VERSION 5.7 ;
  NOWIREEXTENSIONATPIN ON ;
  DIVIDERCHAR "/" ;
  BUSBITCHARS "[]" ;
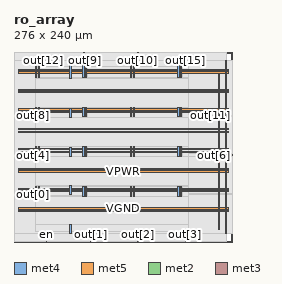
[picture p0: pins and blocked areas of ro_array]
MACRO ro_array
  CLASS BLOCK ;
  FOREIGN ro_array ;
  ORIGIN 0.000 0.000 ;
  SIZE 276.000 BY 240.000 ;
  PIN VGND
    DIRECTION INOUT ;
    USE GROUND ;
    PORT
      LAYER met4 ;
        RECT 30.320 58.040 31.920 70.040 ;
    END
    PORT
      LAYER met4 ;
        RECT 30.320 108.040 31.920 120.040 ;
    END
    PORT
      LAYER met4 ;
        RECT 30.320 158.040 31.920 170.040 ;
    END
    PORT
      LAYER met4 ;
        RECT 30.320 208.040 31.920 228.720 ;
    END
    PORT
      LAYER met4 ;
        RECT 90.320 58.040 91.920 70.040 ;
    END
    PORT
      LAYER met4 ;
        RECT 90.320 108.040 91.920 120.040 ;
    END
    PORT
      LAYER met4 ;
        RECT 90.320 158.040 91.920 170.040 ;
    END
    PORT
      LAYER met4 ;
        RECT 90.320 208.040 91.920 228.720 ;
    END
    PORT
      LAYER met4 ;
        RECT 150.320 58.040 151.920 70.040 ;
    END
    PORT
      LAYER met4 ;
        RECT 150.320 108.040 151.920 120.040 ;
    END
    PORT
      LAYER met4 ;
        RECT 150.320 158.040 151.920 170.040 ;
    END
    PORT
      LAYER met4 ;
        RECT 150.320 208.040 151.920 228.720 ;
    END
    PORT
      LAYER met4 ;
        RECT 210.320 58.040 211.920 70.040 ;
    END
    PORT
      LAYER met4 ;
        RECT 210.320 108.040 211.920 120.040 ;
    END
    PORT
      LAYER met4 ;
        RECT 210.320 158.040 211.920 170.040 ;
    END
    PORT
      LAYER met4 ;
        RECT 210.320 208.040 211.920 228.720 ;
    END
    PORT
      LAYER met5 ;
        RECT 5.520 41.540 270.480 43.140 ;
    END
    PORT
      LAYER met5 ;
        RECT 5.520 66.540 270.480 68.140 ;
    END
    PORT
      LAYER met5 ;
        RECT 5.520 91.540 270.480 93.140 ;
    END
    PORT
      LAYER met5 ;
        RECT 5.520 116.540 270.480 118.140 ;
    END
    PORT
      LAYER met5 ;
        RECT 5.520 141.540 270.480 143.140 ;
    END
    PORT
      LAYER met5 ;
        RECT 5.520 166.540 270.480 168.140 ;
    END
    PORT
      LAYER met5 ;
        RECT 5.520 191.540 270.480 193.140 ;
    END
    PORT
      LAYER met5 ;
        RECT 5.520 216.540 270.480 218.140 ;
    END
    PORT
      LAYER met4 ;
        RECT 70.500 10.640 72.100 22.000 ;
    END
    PORT
      LAYER met4 ;
        RECT 70.500 59.600 72.100 70.960 ;
    END
    PORT
      LAYER met4 ;
        RECT 70.500 108.560 72.100 119.920 ;
    END
    PORT
      LAYER met4 ;
        RECT 70.500 157.520 72.100 168.880 ;
    END
    PORT
      LAYER met4 ;
        RECT 70.500 206.480 72.100 223.280 ;
    END
    PORT
      LAYER met4 ;
        RECT 258.180 16.080 259.780 212.400 ;
    END
  END VGND
  PIN VPWR
    DIRECTION INOUT ;
    USE POWER ;
    PORT
      LAYER met4 ;
        RECT 27.020 58.040 28.620 70.040 ;
    END
    PORT
      LAYER met4 ;
        RECT 27.020 108.040 28.620 120.040 ;
    END
    PORT
      LAYER met4 ;
        RECT 27.020 158.040 28.620 170.040 ;
    END
    PORT
      LAYER met4 ;
        RECT 27.020 208.040 28.620 228.720 ;
    END
    PORT
      LAYER met4 ;
        RECT 87.020 58.040 88.620 70.040 ;
    END
    PORT
      LAYER met4 ;
        RECT 87.020 108.040 88.620 120.040 ;
    END
    PORT
      LAYER met4 ;
        RECT 87.020 158.040 88.620 170.040 ;
    END
    PORT
      LAYER met4 ;
        RECT 87.020 208.040 88.620 228.720 ;
    END
    PORT
      LAYER met4 ;
        RECT 147.020 58.040 148.620 70.040 ;
    END
    PORT
      LAYER met4 ;
        RECT 147.020 108.040 148.620 120.040 ;
    END
    PORT
      LAYER met4 ;
        RECT 147.020 158.040 148.620 170.040 ;
    END
    PORT
      LAYER met4 ;
        RECT 147.020 208.040 148.620 228.720 ;
    END
    PORT
      LAYER met4 ;
        RECT 207.020 58.040 208.620 70.040 ;
    END
    PORT
      LAYER met4 ;
        RECT 207.020 108.040 208.620 120.040 ;
    END
    PORT
      LAYER met4 ;
        RECT 207.020 158.040 208.620 170.040 ;
    END
    PORT
      LAYER met4 ;
        RECT 207.020 208.040 208.620 228.720 ;
    END
    PORT
      LAYER met4 ;
        RECT 267.020 10.640 268.620 228.720 ;
    END
    PORT
      LAYER met5 ;
        RECT 5.520 38.240 270.480 39.840 ;
    END
    PORT
      LAYER met5 ;
        RECT 5.520 63.240 270.480 64.840 ;
    END
    PORT
      LAYER met5 ;
        RECT 5.520 88.240 270.480 89.840 ;
    END
    PORT
      LAYER met5 ;
        RECT 5.520 113.240 270.480 114.840 ;
    END
    PORT
      LAYER met5 ;
        RECT 5.520 138.240 270.480 139.840 ;
    END
    PORT
      LAYER met5 ;
        RECT 5.520 163.240 270.480 164.840 ;
    END
    PORT
      LAYER met5 ;
        RECT 5.520 188.240 270.480 189.840 ;
    END
    PORT
      LAYER met5 ;
        RECT 5.520 213.240 270.480 214.840 ;
    END
  END VPWR
  PIN en
    DIRECTION INPUT ;
    USE SIGNAL ;
    ANTENNAGATEAREA 0.426000 ;
    PORT
      LAYER met2 ;
        RECT 40.570 0.000 40.850 0.280 ;
    END
  END en
  PIN out[0]
    DIRECTION OUTPUT ;
    USE SIGNAL ;
    ANTENNADIFFAREA 0.702900 ;
    PORT
      LAYER met3 ;
        RECT 0.000 59.880 0.600 60.480 ;
    END
  END out[0]
  PIN out[10]
    DIRECTION OUTPUT ;
    USE SIGNAL ;
    ANTENNADIFFAREA 0.702900 ;
    PORT
      LAYER met2 ;
        RECT 155.570 239.720 155.850 240.000 ;
    END
  END out[10]
  PIN out[11]
    DIRECTION OUTPUT ;
    USE SIGNAL ;
    ANTENNADIFFAREA 0.702900 ;
    PORT
      LAYER met3 ;
        RECT 275.400 159.160 276.000 159.760 ;
    END
  END out[11]
  PIN out[12]
    DIRECTION OUTPUT ;
    USE SIGNAL ;
    ANTENNADIFFAREA 0.702900 ;
    PORT
      LAYER met2 ;
        RECT 36.890 239.720 37.170 240.000 ;
    END
  END out[12]
  PIN out[13]
    DIRECTION OUTPUT ;
    USE SIGNAL ;
    ANTENNADIFFAREA 0.702900 ;
    PORT
      LAYER met2 ;
        RECT 88.410 239.720 88.690 240.000 ;
    END
  END out[13]
  PIN out[14]
    DIRECTION OUTPUT ;
    USE SIGNAL ;
    ANTENNADIFFAREA 0.702900 ;
    PORT
      LAYER met2 ;
        RECT 156.490 239.720 156.770 240.000 ;
    END
  END out[14]
  PIN out[15]
    DIRECTION OUTPUT ;
    USE SIGNAL ;
    ANTENNADIFFAREA 0.702900 ;
    PORT
      LAYER met2 ;
        RECT 216.290 239.720 216.570 240.000 ;
    END
  END out[15]
  PIN out[1]
    DIRECTION OUTPUT ;
    USE SIGNAL ;
    ANTENNADIFFAREA 0.702900 ;
    PORT
      LAYER met2 ;
        RECT 96.690 0.000 96.970 0.280 ;
    END
  END out[1]
  PIN out[2]
    DIRECTION OUTPUT ;
    USE SIGNAL ;
    ANTENNADIFFAREA 0.702900 ;
    PORT
      LAYER met2 ;
        RECT 156.490 0.000 156.770 0.280 ;
    END
  END out[2]
  PIN out[3]
    DIRECTION OUTPUT ;
    USE SIGNAL ;
    ANTENNADIFFAREA 0.702900 ;
    PORT
      LAYER met2 ;
        RECT 216.290 0.000 216.570 0.280 ;
    END
  END out[3]
  PIN out[4]
    DIRECTION OUTPUT ;
    USE SIGNAL ;
    ANTENNADIFFAREA 0.702900 ;
    PORT
      LAYER met3 ;
        RECT 0.000 108.840 0.600 109.440 ;
    END
  END out[4]
  PIN out[5]
    DIRECTION OUTPUT ;
    USE SIGNAL ;
    ANTENNADIFFAREA 0.702900 ;
    PORT
      LAYER met3 ;
        RECT 0.000 110.200 0.600 110.800 ;
    END
  END out[5]
  PIN out[6]
    DIRECTION OUTPUT ;
    USE SIGNAL ;
    ANTENNADIFFAREA 0.702900 ;
    PORT
      LAYER met3 ;
        RECT 275.400 108.840 276.000 109.440 ;
    END
  END out[6]
  PIN out[7]
    DIRECTION OUTPUT ;
    USE SIGNAL ;
    ANTENNADIFFAREA 0.702900 ;
    PORT
      LAYER met3 ;
        RECT 275.400 110.200 276.000 110.800 ;
    END
  END out[7]
  PIN out[8]
    DIRECTION OUTPUT ;
    USE SIGNAL ;
    ANTENNADIFFAREA 0.702900 ;
    PORT
      LAYER met3 ;
        RECT 0.000 159.160 0.600 159.760 ;
    END
  END out[8]
  PIN out[9]
    DIRECTION OUTPUT ;
    USE SIGNAL ;
    ANTENNADIFFAREA 0.702900 ;
    PORT
      LAYER met2 ;
        RECT 89.330 239.720 89.610 240.000 ;
    END
  END out[9]
  OBS
      LAYER nwell ;
        RECT 5.330 10.795 270.670 228.565 ;
      LAYER li1 ;
        RECT 5.520 10.795 270.480 228.565 ;
      LAYER met1 ;
        RECT 0.990 10.640 270.480 228.720 ;
      LAYER met2 ;
        RECT 1.010 239.440 36.610 239.930 ;
        RECT 37.450 239.440 88.130 239.930 ;
        RECT 88.970 239.440 89.050 239.930 ;
        RECT 89.890 239.440 155.290 239.930 ;
        RECT 156.130 239.440 156.210 239.930 ;
        RECT 157.050 239.440 216.010 239.930 ;
        RECT 216.850 239.440 269.010 239.930 ;
        RECT 1.010 0.560 269.010 239.440 ;
        RECT 1.010 0.070 40.290 0.560 ;
        RECT 41.130 0.070 96.410 0.560 ;
        RECT 97.250 0.070 156.210 0.560 ;
        RECT 157.050 0.070 216.010 0.560 ;
        RECT 216.850 0.070 269.010 0.560 ;
      LAYER met3 ;
        RECT 0.600 160.160 275.400 228.645 ;
        RECT 1.000 158.760 275.000 160.160 ;
        RECT 0.600 111.200 275.400 158.760 ;
        RECT 1.000 108.440 275.000 111.200 ;
        RECT 0.600 60.880 275.400 108.440 ;
        RECT 1.000 59.480 275.400 60.880 ;
        RECT 0.600 10.715 275.400 59.480 ;
      LAYER met4 ;
        RECT 29.020 207.640 29.920 221.505 ;
        RECT 32.320 207.640 70.100 221.505 ;
        RECT 27.020 206.080 70.100 207.640 ;
        RECT 72.500 207.640 86.620 221.505 ;
        RECT 89.020 207.640 89.920 221.505 ;
        RECT 92.320 207.640 146.620 221.505 ;
        RECT 149.020 207.640 149.920 221.505 ;
        RECT 152.320 207.640 206.620 221.505 ;
        RECT 209.020 207.640 209.920 221.505 ;
        RECT 212.320 207.640 220.505 221.505 ;
        RECT 72.500 206.080 220.505 207.640 ;
        RECT 27.020 170.440 220.505 206.080 ;
        RECT 29.020 157.640 29.920 170.440 ;
        RECT 32.320 169.280 86.620 170.440 ;
        RECT 32.320 157.640 70.100 169.280 ;
        RECT 27.020 157.120 70.100 157.640 ;
        RECT 72.500 157.640 86.620 169.280 ;
        RECT 89.020 157.640 89.920 170.440 ;
        RECT 92.320 157.640 146.620 170.440 ;
        RECT 149.020 157.640 149.920 170.440 ;
        RECT 152.320 157.640 206.620 170.440 ;
        RECT 209.020 157.640 209.920 170.440 ;
        RECT 212.320 157.640 220.505 170.440 ;
        RECT 72.500 157.120 220.505 157.640 ;
        RECT 27.020 120.440 220.505 157.120 ;
        RECT 29.020 107.640 29.920 120.440 ;
        RECT 32.320 120.320 86.620 120.440 ;
        RECT 32.320 108.160 70.100 120.320 ;
        RECT 72.500 108.160 86.620 120.320 ;
        RECT 32.320 107.640 86.620 108.160 ;
        RECT 89.020 107.640 89.920 120.440 ;
        RECT 92.320 107.640 146.620 120.440 ;
        RECT 149.020 107.640 149.920 120.440 ;
        RECT 152.320 107.640 206.620 120.440 ;
        RECT 209.020 107.640 209.920 120.440 ;
        RECT 212.320 107.640 220.505 120.440 ;
        RECT 27.020 71.360 220.505 107.640 ;
        RECT 27.020 70.440 70.100 71.360 ;
        RECT 29.020 57.640 29.920 70.440 ;
        RECT 32.320 59.200 70.100 70.440 ;
        RECT 72.500 70.440 220.505 71.360 ;
        RECT 72.500 59.200 86.620 70.440 ;
        RECT 32.320 57.640 86.620 59.200 ;
        RECT 89.020 57.640 89.920 70.440 ;
        RECT 92.320 57.640 146.620 70.440 ;
        RECT 149.020 57.640 149.920 70.440 ;
        RECT 152.320 57.640 206.620 70.440 ;
        RECT 209.020 57.640 209.920 70.440 ;
        RECT 212.320 57.640 220.505 70.440 ;
        RECT 27.020 22.400 220.505 57.640 ;
        RECT 27.020 13.095 70.100 22.400 ;
        RECT 72.500 13.095 220.505 22.400 ;
  END
END ro_array
END LIBRARY

